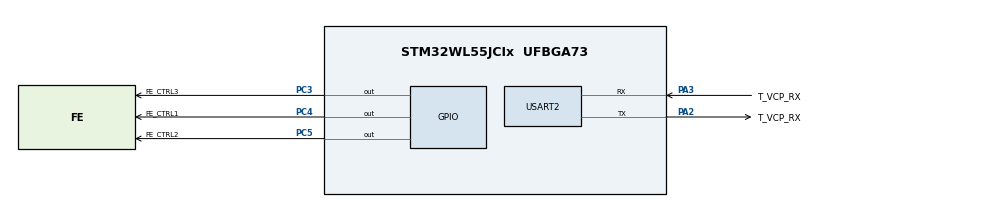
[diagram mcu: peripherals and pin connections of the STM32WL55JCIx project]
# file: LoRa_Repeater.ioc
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Dma.Request0=USART2_RX
Dma.Request1=USART2_TX
Dma.USART2_RX.0.Channel_PRIV_NPRIV=DMA_CHANNEL_NPRIV_DISABLE
Dma.USART2_RX.0.Direction=DMA_PERIPH_TO_MEMORY
Dma.USART2_RX.0.EventEnable=DISABLE
Dma.USART2_RX.0.Instance=DMA1_Channel1
Dma.USART2_RX.0.MemDataAlignment=DMA_MDATAALIGN_BYTE
Dma.USART2_RX.0.MemInc=DMA_MINC_ENABLE
Dma.USART2_RX.0.Mode=DMA_CIRCULAR
Dma.USART2_RX.0.PeriphDataAlignment=DMA_PDATAALIGN_BYTE
Dma.USART2_RX.0.PeriphInc=DMA_PINC_DISABLE
Dma.USART2_RX.0.Polarity=HAL_DMAMUX_REQ_GEN_RISING
Dma.USART2_RX.0.Priority=DMA_PRIORITY_LOW
Dma.USART2_RX.0.RequestNumber=1
Dma.USART2_RX.0.SignalID=NONE
Dma.USART2_RX.0.SyncEnable=DISABLE
Dma.USART2_RX.0.SyncPolarity=HAL_DMAMUX_SYNC_NO_EVENT
Dma.USART2_RX.0.SyncRequestNumber=1
Dma.USART2_RX.0.SyncSignalID=NONE
Dma.USART2_TX.1.Channel_PRIV_NPRIV=DMA_CHANNEL_NPRIV_DISABLE
Dma.USART2_TX.1.Direction=DMA_MEMORY_TO_PERIPH
Dma.USART2_TX.1.EventEnable=DISABLE
Dma.USART2_TX.1.Instance=DMA1_Channel2
Dma.USART2_TX.1.MemDataAlignment=DMA_MDATAALIGN_BYTE
Dma.USART2_TX.1.MemInc=DMA_MINC_ENABLE
Dma.USART2_TX.1.Mode=DMA_CIRCULAR
Dma.USART2_TX.1.PeriphDataAlignment=DMA_PDATAALIGN_BYTE
Dma.USART2_TX.1.PeriphInc=DMA_PINC_DISABLE
Dma.USART2_TX.1.Polarity=HAL_DMAMUX_REQ_GEN_RISING
Dma.USART2_TX.1.Priority=DMA_PRIORITY_LOW
Dma.USART2_TX.1.RequestNumber=1
Dma.USART2_TX.1.SignalID=NONE
Dma.USART2_TX.1.SyncEnable=DISABLE
Dma.USART2_TX.1.SyncPolarity=HAL_DMAMUX_SYNC_NO_EVENT
Dma.USART2_TX.1.SyncRequestNumber=1
Dma.USART2_TX.1.SyncSignalID=NONE
Mcu.Family=STM32WL
Mcu.Name=STM32WL55JCIx
Mcu.Package=UFBGA73
NVIC.DMA1_Channel1_IRQn=true\:0\:0\:false\:false\:true\:false\:true\:true
NVIC.DMA1_Channel2_IRQn=true\:0\:0\:false\:false\:true\:false\:true\:true
NVIC.PriorityGroup=NVIC_PRIORITYGROUP_4
NVIC.SUBGHZ_Radio_IRQn=true\:0\:0\:false\:false\:true\:true\:true\:true
NVIC.USART2_IRQn=true\:0\:0\:false\:false\:true\:true\:true\:true
PA2.GPIO_Label=T_VCP_RX
PA2.Mode=Asynchronous
PA2.Signal=USART2_TX
PA3.GPIO_Label=T_VCP_RX
PA3.Mode=Asynchronous
PA3.Signal=USART2_RX
PC14-OSC32_IN.GPIO_Label=RCC_OSC32_IN
PC14-OSC32_IN.Signal=RCC_OSC32_IN
PC15-OSC32_OUT.GPIO_Label=RCC_OSC32_OUT
PC15-OSC32_OUT.Signal=RCC_OSC32_OUT
PC3.GPIO_Label=FE_CTRL3
PC3.GPIO_Speed=GPIO_SPEED_FREQ_VERY_HIGH
PC3.Signal=GPIO_Output
PC4.GPIO_Label=FE_CTRL1
PC4.GPIO_Speed=GPIO_SPEED_FREQ_VERY_HIGH
PC4.Signal=GPIO_Output
PC5.GPIO_Label=FE_CTRL2
PC5.GPIO_Speed=GPIO_SPEED_FREQ_VERY_HIGH
PC5.Signal=GPIO_Output
ProjectManager.HeapSize=0x200
ProjectManager.StackSize=0x400
ProjectManager.TargetToolchain=STM32CubeIDE
RCC.HSE_VALUE=32000000
RCC.HSI_VALUE=16000000
RCC.LSE_VALUE=32768
RCC.VCOOutputFreq_Value=32000000
USART2.VirtualMode-Asynchronous=VM_ASYNC
VP_SUBGHZ_VS_SUBGHZ.Mode=SUBGHZ_Activate
board=NUCLEO-WL55JC1

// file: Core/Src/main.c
/* ============================================================================
 * Firmware da Placa 2 - LoRa_Base (ESTAÇÃO BASE) - Versão Receptor Puro
 * ============================================================================
 * Versão: 3.0
 * Autor: Gemini
 * Data: 9 de Outubro de 2025
 *
 * NOTA DA VERSÃO:
 * Este firmware foi simplificado para atuar como um receptor dedicado.
 * A lógica de envio de comandos, menus de usuário e gerenciamento de
 * timeouts foi removida.
 *
 * 1. O rádio LoRa é colocado em modo de recepção contínua na inicialização.
 * 2. O MCU entra em modo de baixo consumo (Sleep) e aguarda a interrupção
 * do rádio (IRQ_RX_DONE).
 * 3. Ao receber um pacote, ele o decodifica e exibe os dados de telemetria
 * no terminal serial do PC.
 * 4. Imediatamente após, volta ao modo de recepção para aguardar o próximo
 * pacote.
 * ========================================================================= */

#include "main.h"
#include "dma.h"
#include "subghz.h"
#include "usart.h"
#include "gpio.h"

/* USER CODE BEGIN Includes */
#include "stm32wlxx_nucleo.h"
#include <string.h>
#include <stdio.h>
#include <stdbool.h>
#include "radio_driver.h"
#include "protocol.h"
/* USER CODE END Includes */

/* USER CODE BEGIN PV */
static uint8_t lora_rx_buffer[TELEMETRY_PAYLOAD_SIZE]; // Buffer para receber telemetria

const RadioLoRaBandwidths_t Bandwidths[] = { LORA_BW_125, LORA_BW_250, LORA_BW_500 };
/* USER CODE END PV */

void SystemClock_Config(void);
/* USER CODE BEGIN PFP */
void Radio_Init(void);
void ProcessTelemetryResponse(uint8_t* buffer, uint8_t size);
void RadioOnDioIrq(RadioIrqMasks_t radioIrq);
/* USER CODE END PFP */

/* USER CODE BEGIN 0 */
// Redireciona a saída do printf para a USART2 (nossa porta de debug para o PC)
int _write(int file, char *ptr, int len)
{
  HAL_UART_Transmit(&huart2, (uint8_t*)ptr, len, HAL_MAX_DELAY);
  return len;
}
/* USER CODE END 0 */

int main(void)
{
  /* MCU Configuration--------------------------------------------------------*/
  HAL_Init();
  SystemClock_Config();
  MX_GPIO_Init();
  MX_DMA_Init();
  MX_SUBGHZ_Init();
  MX_USART2_UART_Init();

  /* USER CODE BEGIN 2 */
  BSP_LED_Init(LED_GREEN);

  //printf("\r\n--- LoRa_Base (ESTACAO BASE) ---\r\n");
  //printf("Modo: Receptor Puro\r\n");

  Radio_Init();
  //printf("Radio LoRa inicializado. Aguardando telemetria...\r\n");
  /* USER CODE END 2 */

  /* Infinite loop */
  /* USER CODE BEGIN WHILE */
  while (1)
  {
    // O processamento acontece 100% no callback de interrupção do rádio.
    // O processador pode entrar em modo sleep para economizar energia.
    HAL_PWR_EnterSLEEPMode(PWR_MAINREGULATOR_ON, PWR_SLEEPENTRY_WFI);
  }
  /* USER CODE END WHILE */
}

void SystemClock_Config(void)
{
  RCC_OscInitTypeDef RCC_OscInitStruct = {0};
  RCC_ClkInitTypeDef RCC_ClkInitStruct = {0};

  __HAL_PWR_VOLTAGESCALING_CONFIG(PWR_REGULATOR_VOLTAGE_SCALE1);

  RCC_OscInitStruct.OscillatorType = RCC_OSCILLATORTYPE_MSI;
  RCC_OscInitStruct.MSIState = RCC_MSI_ON;
  RCC_OscInitStruct.MSICalibrationValue = RCC_MSICALIBRATION_DEFAULT;
  RCC_OscInitStruct.MSIClockRange = RCC_MSIRANGE_6;
  RCC_OscInitStruct.PLL.PLLState = RCC_PLL_ON;
  RCC_OscInitStruct.PLL.PLLSource = RCC_PLLSOURCE_MSI;
  RCC_OscInitStruct.PLL.PLLM = 1;
  RCC_OscInitStruct.PLL.PLLN = 24;
  RCC_OscInitStruct.PLL.PLLP = RCC_PLLP_DIV2;
  RCC_OscInitStruct.PLL.PLLQ = RCC_PLLQ_DIV2;
  RCC_OscInitStruct.PLL.PLLR = RCC_PLLR_DIV2;
  if (HAL_RCC_OscConfig(&RCC_OscInitStruct) != HAL_OK)
  {
    Error_Handler();
  }

  RCC_ClkInitStruct.ClockType = RCC_CLOCKTYPE_HCLK|RCC_CLOCKTYPE_SYSCLK
                              |RCC_CLOCKTYPE_PCLK1|RCC_CLOCKTYPE_PCLK2;
  RCC_ClkInitStruct.SYSCLKSource = RCC_SYSCLKSOURCE_PLLCLK;
  RCC_ClkInitStruct.AHBCLKDivider = RCC_SYSCLK_DIV1;
  RCC_ClkInitStruct.APB1CLKDivider = RCC_HCLK_DIV1;
  RCC_ClkInitStruct.APB2CLKDivider = RCC_HCLK_DIV1;

  if (HAL_RCC_ClockConfig(&RCC_ClkInitStruct, FLASH_LATENCY_2) != HAL_OK)
  {
    Error_Handler();
  }
}

/* USER CODE BEGIN 4 */

/**
  * @brief Decodifica e exibe o pacote de telemetria recebido.
  */
void ProcessTelemetryResponse(uint8_t* buffer, uint8_t size)
{
	printf("FFFFFFFFFFFFFFFFFF\r\n");
    if (size != TELEMETRY_PAYLOAD_SIZE) {
        //printf("ERRO: Pacote com tamanho inesperado: %d (esperado: %d)\r\n", size, TELEMETRY_PAYLOAD_SIZE);
        return;
    }

    LoRaPayload_t telemetry_data;
    memcpy(&telemetry_data, buffer, sizeof(LoRaPayload_t));

    float latitude = telemetry_data.latitude_raw / 10000000.0f;
    float longitude = telemetry_data.longitude_raw / 10000000.0f;
    float altitude_m = telemetry_data.altitude_raw / 1000.0f;

    bool gpsFixOK = (telemetry_data.sats_and_fix >> 7) & 0x01;
    uint8_t satCount = telemetry_data.sats_and_fix & 0x7F;

    printf("{\"ID\": %lu, \"Lat\": %.7f, \"Lon\": %.7f, \"Alt\": %.2f, \"Volt\": %u, \"Temp\": %d, \"GPS\": \"%s\", \"Sats\": %u}\r\n", telemetry_data.packet_id, latitude, longitude, altitude_m, telemetry_data.voltage_mv, telemetry_data.radio_temp_c, gpsFixOK ? "FIX OK" : "NO FIX", satCount);
}

/**
  * @brief Inicializa o rádio Sub-GHz e o coloca em modo de recepção contínua.
  */
void Radio_Init(void)
{
    SUBGRF_Init(RadioOnDioIrq);

    SUBGRF_SetStandby(STDBY_RC);
    SUBGRF_SetPacketType(PACKET_TYPE_LORA);
    SUBGRF_SetRfFrequency(RF_FREQUENCY);
    SUBGRF_SetRfTxPower(TX_OUTPUT_POWER);

    ModulationParams_t modulationParams;
    modulationParams.PacketType = PACKET_TYPE_LORA;
    modulationParams.Params.LoRa.SpreadingFactor = LORA_SPREADING_FACTOR;
    modulationParams.Params.LoRa.Bandwidth = Bandwidths[LORA_BANDWIDTH];
    modulationParams.Params.LoRa.CodingRate = LORA_CODINGRATE;
    modulationParams.Params.LoRa.LowDatarateOptimize = 0x00;
    SUBGRF_SetModulationParams(&modulationParams);

    // Configuração para receber pacotes de telemetria
    PacketParams_t packetParams;
    packetParams.PacketType = PACKET_TYPE_LORA;
    packetParams.Params.LoRa.PreambleLength = LORA_PREAMBLE_LENGTH;
    packetParams.Params.LoRa.HeaderType = LORA_PACKET_FIXED_LENGTH;
    packetParams.Params.LoRa.PayloadLength = TELEMETRY_PAYLOAD_SIZE; // <-- Ponto chave!
    packetParams.Params.LoRa.CrcMode = LORA_CRC_ON;
    packetParams.Params.LoRa.InvertIQ = LORA_IQ_NORMAL;
    SUBGRF_SetPacketParams(&packetParams);

    // Configura interrupções apenas para eventos de recepção
    SUBGRF_SetDioIrqParams(IRQ_RX_DONE | IRQ_CRC_ERROR | IRQ_RX_TX_TIMEOUT | IRQ_TX_DONE,
                           IRQ_RX_DONE | IRQ_CRC_ERROR | IRQ_RX_TX_TIMEOUT | IRQ_TX_DONE,
                           IRQ_RADIO_NONE, IRQ_RADIO_NONE);

    // Inicia em modo de recepção contínua
    SUBGRF_SetRx(0);
}

/**
  * @brief Radio Interuption Callback. Handles both RX and TX events
  */
void RadioOnDioIrq(RadioIrqMasks_t radioIrq)
{
    switch (radioIrq)
    {
        case IRQ_RX_DONE:
            {
                uint8_t received_size = 0;
                //PacketStatus_t packetStatus;
                printf("Jevous!\r\n");

                BSP_LED_Toggle(LED_GREEN);

                SUBGRF_GetPayload(lora_rx_buffer, &received_size, TELEMETRY_PAYLOAD_SIZE);
                //SUBGRF_GetPacketStatus(&packetStatus);

                //printf("\r\nPacote LoRa Recebido! RSSI: %d dBm, SNR: %d\r\n",
                      //packetStatus.Params.LoRa.RssiPkt, packetStatus.Params.LoRa.SnrPkt);

                // Repeater Node wont process packets today :D
                //ProcessTelemetryResponse(lora_rx_buffer, received_size);

                SUBGRF_SetTx(0);
                SUBGRF_SendPayload(lora_rx_buffer, received_size, 0);
            }
            break;

        case IRQ_TX_DONE:
            // Volta para o modo de recepção para aguardar o próximo pacote
        	printf("IRQ_TX_DONE!\r\n");
            SUBGRF_SetRx(0);
            break;

        case IRQ_CRC_ERROR:
            printf("WARN: Erro de CRC no pacote LoRa.\r\n");
            SUBGRF_SetRx(0); // Volta a escutar
            break;

        case IRQ_RX_TX_TIMEOUT:
            printf("WARN: Timeout de recepção LoRa.\r\n");
            SUBGRF_SetRx(0); // Volta a escutar
            break;

        default:
            break;
    }
}
/* USER CODE END 4 */

void Error_Handler(void)
{
  __disable_irq();
  while (1)
  {
  }
}
